VERSION 5.7 ;
  NOWIREEXTENSIONATPIN ON ;
  DIVIDERCHAR "/" ;
  BUSBITCHARS "[]" ;
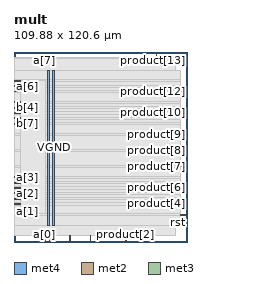
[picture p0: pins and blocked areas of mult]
MACRO mult
  CLASS BLOCK ;
  FOREIGN mult ;
  ORIGIN 0.000 0.000 ;
  SIZE 109.880 BY 120.600 ;
  PIN VGND
    DIRECTION INOUT ;
    USE GROUND ;
    PORT
      LAYER met4 ;
        RECT 24.340 10.640 25.940 109.040 ;
    END
  END VGND
  PIN VPWR
    DIRECTION INOUT ;
    USE POWER ;
    PORT
      LAYER met4 ;
        RECT 21.040 10.640 22.640 109.040 ;
    END
  END VPWR
  PIN a[0]
    DIRECTION INPUT ;
    USE SIGNAL ;
    ANTENNAGATEAREA 0.196500 ;
    PORT
      LAYER met2 ;
        RECT 19.410 0.000 19.690 4.000 ;
    END
  END a[0]
  PIN a[1]
    DIRECTION INPUT ;
    USE SIGNAL ;
    ANTENNAGATEAREA 0.196500 ;
    PORT
      LAYER met3 ;
        RECT 0.000 23.840 4.000 24.440 ;
    END
  END a[1]
  PIN a[2]
    DIRECTION INPUT ;
    USE SIGNAL ;
    ANTENNAGATEAREA 0.196500 ;
    PORT
      LAYER met3 ;
        RECT 0.000 30.640 4.000 31.240 ;
    END
  END a[2]
  PIN a[3]
    DIRECTION INPUT ;
    USE SIGNAL ;
    ANTENNAGATEAREA 0.196500 ;
    PORT
      LAYER met3 ;
        RECT 0.000 40.840 4.000 41.440 ;
    END
  END a[3]
  PIN a[4]
    DIRECTION INPUT ;
    USE SIGNAL ;
    ANTENNAGATEAREA 0.196500 ;
    PORT
      LAYER met3 ;
        RECT 0.000 78.240 4.000 78.840 ;
    END
  END a[4]
  PIN a[5]
    DIRECTION INPUT ;
    USE SIGNAL ;
    ANTENNAGATEAREA 0.196500 ;
    PORT
      LAYER met3 ;
        RECT 0.000 88.440 4.000 89.040 ;
    END
  END a[5]
  PIN a[6]
    DIRECTION INPUT ;
    USE SIGNAL ;
    ANTENNAGATEAREA 0.196500 ;
    PORT
      LAYER met3 ;
        RECT 0.000 98.640 4.000 99.240 ;
    END
  END a[6]
  PIN a[7]
    DIRECTION INPUT ;
    USE SIGNAL ;
    ANTENNAGATEAREA 0.196500 ;
    PORT
      LAYER met2 ;
        RECT 19.410 116.600 19.690 120.600 ;
    END
  END a[7]
  PIN b[0]
    DIRECTION INPUT ;
    USE SIGNAL ;
    ANTENNAGATEAREA 0.196500 ;
    PORT
      LAYER met3 ;
        RECT 0.000 27.240 4.000 27.840 ;
    END
  END b[0]
  PIN b[1]
    DIRECTION INPUT ;
    USE SIGNAL ;
    ANTENNAGATEAREA 0.196500 ;
    PORT
      LAYER met2 ;
        RECT 22.630 0.000 22.910 4.000 ;
    END
  END b[1]
  PIN b[2]
    DIRECTION INPUT ;
    USE SIGNAL ;
    ANTENNAGATEAREA 0.196500 ;
    PORT
      LAYER met3 ;
        RECT 0.000 34.040 4.000 34.640 ;
    END
  END b[2]
  PIN b[3]
    DIRECTION INPUT ;
    USE SIGNAL ;
    ANTENNAGATEAREA 0.196500 ;
    PORT
      LAYER met3 ;
        RECT 0.000 37.440 4.000 38.040 ;
    END
  END b[3]
  PIN b[4]
    DIRECTION INPUT ;
    USE SIGNAL ;
    ANTENNAGATEAREA 0.196500 ;
    PORT
      LAYER met3 ;
        RECT 0.000 85.040 4.000 85.640 ;
    END
  END b[4]
  PIN b[5]
    DIRECTION INPUT ;
    USE SIGNAL ;
    ANTENNAGATEAREA 0.196500 ;
    PORT
      LAYER met3 ;
        RECT 0.000 95.240 4.000 95.840 ;
    END
  END b[5]
  PIN b[6]
    DIRECTION INPUT ;
    USE SIGNAL ;
    ANTENNAGATEAREA 0.196500 ;
    PORT
      LAYER met3 ;
        RECT 0.000 81.640 4.000 82.240 ;
    END
  END b[6]
  PIN b[7]
    DIRECTION INPUT ;
    USE SIGNAL ;
    ANTENNAGATEAREA 0.196500 ;
    PORT
      LAYER met3 ;
        RECT 0.000 74.840 4.000 75.440 ;
    END
  END b[7]
  PIN clk
    DIRECTION INPUT ;
    USE SIGNAL ;
    ANTENNAGATEAREA 0.852000 ;
    PORT
      LAYER met3 ;
        RECT 0.000 102.040 4.000 102.640 ;
    END
  END clk
  PIN product[0]
    DIRECTION OUTPUT ;
    USE SIGNAL ;
    ANTENNADIFFAREA 0.445500 ;
    PORT
      LAYER met2 ;
        RECT 35.510 0.000 35.790 4.000 ;
    END
  END product[0]
  PIN product[10]
    DIRECTION OUTPUT ;
    USE SIGNAL ;
    ANTENNADIFFAREA 0.445500 ;
    PORT
      LAYER met3 ;
        RECT 105.880 81.640 109.880 82.240 ;
    END
  END product[10]
  PIN product[11]
    DIRECTION OUTPUT ;
    USE SIGNAL ;
    ANTENNADIFFAREA 0.445500 ;
    PORT
      LAYER met3 ;
        RECT 105.880 85.040 109.880 85.640 ;
    END
  END product[11]
  PIN product[12]
    DIRECTION OUTPUT ;
    USE SIGNAL ;
    ANTENNADIFFAREA 0.445500 ;
    PORT
      LAYER met3 ;
        RECT 105.880 95.240 109.880 95.840 ;
    END
  END product[12]
  PIN product[13]
    DIRECTION OUTPUT ;
    USE SIGNAL ;
    ANTENNADIFFAREA 0.445500 ;
    PORT
      LAYER met2 ;
        RECT 90.250 116.600 90.530 120.600 ;
    END
  END product[13]
  PIN product[14]
    DIRECTION OUTPUT ;
    USE SIGNAL ;
    ANTENNADIFFAREA 0.445500 ;
    PORT
      LAYER met2 ;
        RECT 93.470 116.600 93.750 120.600 ;
    END
  END product[14]
  PIN product[15]
    DIRECTION OUTPUT ;
    USE SIGNAL ;
    ANTENNADIFFAREA 0.445500 ;
    PORT
      LAYER met2 ;
        RECT 83.810 116.600 84.090 120.600 ;
    END
  END product[15]
  PIN product[1]
    DIRECTION OUTPUT ;
    USE SIGNAL ;
    ANTENNADIFFAREA 0.445500 ;
    PORT
      LAYER met2 ;
        RECT 48.390 0.000 48.670 4.000 ;
    END
  END product[1]
  PIN product[2]
    DIRECTION OUTPUT ;
    USE SIGNAL ;
    ANTENNADIFFAREA 0.445500 ;
    PORT
      LAYER met2 ;
        RECT 70.930 0.000 71.210 4.000 ;
    END
  END product[2]
  PIN product[3]
    DIRECTION OUTPUT ;
    USE SIGNAL ;
    ANTENNADIFFAREA 0.445500 ;
    PORT
      LAYER met2 ;
        RECT 80.590 0.000 80.870 4.000 ;
    END
  END product[3]
  PIN product[4]
    DIRECTION OUTPUT ;
    USE SIGNAL ;
    ANTENNADIFFAREA 0.445500 ;
    PORT
      LAYER met3 ;
        RECT 105.880 23.840 109.880 24.440 ;
    END
  END product[4]
  PIN product[5]
    DIRECTION OUTPUT ;
    USE SIGNAL ;
    ANTENNADIFFAREA 0.445500 ;
    PORT
      LAYER met3 ;
        RECT 105.880 27.240 109.880 27.840 ;
    END
  END product[5]
  PIN product[6]
    DIRECTION OUTPUT ;
    USE SIGNAL ;
    ANTENNADIFFAREA 0.445500 ;
    PORT
      LAYER met3 ;
        RECT 105.880 34.040 109.880 34.640 ;
    END
  END product[6]
  PIN product[7]
    DIRECTION OUTPUT ;
    USE SIGNAL ;
    ANTENNADIFFAREA 0.445500 ;
    PORT
      LAYER met3 ;
        RECT 105.880 47.640 109.880 48.240 ;
    END
  END product[7]
  PIN product[8]
    DIRECTION OUTPUT ;
    USE SIGNAL ;
    ANTENNADIFFAREA 0.445500 ;
    PORT
      LAYER met3 ;
        RECT 105.880 57.840 109.880 58.440 ;
    END
  END product[8]
  PIN product[9]
    DIRECTION OUTPUT ;
    USE SIGNAL ;
    ANTENNADIFFAREA 0.445500 ;
    PORT
      LAYER met3 ;
        RECT 105.880 68.040 109.880 68.640 ;
    END
  END product[9]
  PIN rst
    DIRECTION INPUT ;
    USE SIGNAL ;
    ANTENNAGATEAREA 0.213000 ;
    PORT
      LAYER met3 ;
        RECT 105.880 17.040 109.880 17.640 ;
    END
  END rst
  OBS
      LAYER nwell ;
        RECT 5.330 10.795 104.150 108.885 ;
      LAYER li1 ;
        RECT 5.520 10.795 103.960 108.885 ;
      LAYER met1 ;
        RECT 0.530 10.640 104.260 109.040 ;
      LAYER met2 ;
        RECT 0.550 116.320 19.130 117.370 ;
        RECT 19.970 116.320 83.530 117.370 ;
        RECT 84.370 116.320 89.970 117.370 ;
        RECT 90.810 116.320 93.190 117.370 ;
        RECT 94.030 116.320 102.480 117.370 ;
        RECT 0.550 4.280 102.480 116.320 ;
        RECT 0.550 4.000 19.130 4.280 ;
        RECT 19.970 4.000 22.350 4.280 ;
        RECT 23.190 4.000 35.230 4.280 ;
        RECT 36.070 4.000 48.110 4.280 ;
        RECT 48.950 4.000 70.650 4.280 ;
        RECT 71.490 4.000 80.310 4.280 ;
        RECT 81.150 4.000 102.480 4.280 ;
      LAYER met3 ;
        RECT 0.525 103.040 105.880 108.965 ;
        RECT 4.400 101.640 105.880 103.040 ;
        RECT 0.525 99.640 105.880 101.640 ;
        RECT 4.400 98.240 105.880 99.640 ;
        RECT 0.525 96.240 105.880 98.240 ;
        RECT 4.400 94.840 105.480 96.240 ;
        RECT 0.525 89.440 105.880 94.840 ;
        RECT 4.400 88.040 105.880 89.440 ;
        RECT 0.525 86.040 105.880 88.040 ;
        RECT 4.400 84.640 105.480 86.040 ;
        RECT 0.525 82.640 105.880 84.640 ;
        RECT 4.400 81.240 105.480 82.640 ;
        RECT 0.525 79.240 105.880 81.240 ;
        RECT 4.400 77.840 105.880 79.240 ;
        RECT 0.525 75.840 105.880 77.840 ;
        RECT 4.400 74.440 105.880 75.840 ;
        RECT 0.525 69.040 105.880 74.440 ;
        RECT 0.525 67.640 105.480 69.040 ;
        RECT 0.525 58.840 105.880 67.640 ;
        RECT 0.525 57.440 105.480 58.840 ;
        RECT 0.525 48.640 105.880 57.440 ;
        RECT 0.525 47.240 105.480 48.640 ;
        RECT 0.525 41.840 105.880 47.240 ;
        RECT 4.400 40.440 105.880 41.840 ;
        RECT 0.525 38.440 105.880 40.440 ;
        RECT 4.400 37.040 105.880 38.440 ;
        RECT 0.525 35.040 105.880 37.040 ;
        RECT 4.400 33.640 105.480 35.040 ;
        RECT 0.525 31.640 105.880 33.640 ;
        RECT 4.400 30.240 105.880 31.640 ;
        RECT 0.525 28.240 105.880 30.240 ;
        RECT 4.400 26.840 105.480 28.240 ;
        RECT 0.525 24.840 105.880 26.840 ;
        RECT 4.400 23.440 105.480 24.840 ;
        RECT 0.525 18.040 105.880 23.440 ;
        RECT 0.525 16.640 105.480 18.040 ;
        RECT 0.525 10.715 105.880 16.640 ;
      LAYER met4 ;
        RECT 3.975 17.855 19.945 102.505 ;
  END
END mult
END LIBRARY

